# 
# LEF OUT 
# User Name : lonawu 
# Date : Thu Oct 12 15:11:58 2023
# 
VERSION 5.6 ;
BUSBITCHARS "[]" ;
DIVIDERCHAR "/" ;

UNITS
  DATABASE MICRONS 1000 ;
END UNITS
MANUFACTURINGGRID 0.001 ;

LAYER 3P
  TYPE MASTERSLICE ;
END 3P

LAYER 3N
  TYPE MASTERSLICE ;
END 3N

LAYER 2P
  TYPE MASTERSLICE ;
END 2P

LAYER 2N
  TYPE MASTERSLICE ;
END 2N

LAYER 1F_ACT
  TYPE MASTERSLICE ;
END 1F_ACT

LAYER 1G_GATE
  TYPE MASTERSLICE ;
END 1G_GATE

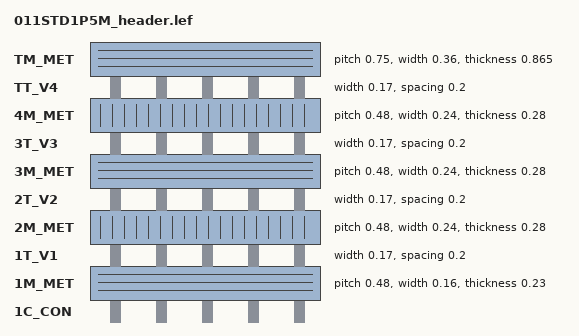
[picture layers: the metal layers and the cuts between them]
LAYER 1C_CON
  TYPE CUT ;
  WIDTH 0 ;
END 1C_CON

LAYER 1M_MET
  TYPE ROUTING ;
  DIRECTION HORIZONTAL ;
  PITCH 0.48 ;
  WIDTH 0.16 ;
  AREA 0.144 ;
  SPACINGTABLE 
    PARALLELRUNLENGTH    0      0      
      WIDTH 0           0.15   0.18   
      WIDTH 0.399       0.18   0.18   ;
  MINWIDTH 0.16 ;
  RESISTANCE RPERSQ 0.26 ;
  CAPACITANCE CPERSQDIST 4.7e-05 ;
  THICKNESS 0.23 ;
  ANTENNACUMAREARATIO 400 ;
  ANTENNACUMDIFFAREARATIO PWL ( ( 0 400 ) ( 0.2 400 ) ( 0.201 2280.4 ) ( 1.2 2680 )  ) ;
END 1M_MET

LAYER 1T_V1
  TYPE CUT ;
  SPACING 0.2 ;
  WIDTH 0.17 ;
  ANTENNACUMAREARATIO 20 ;
  ANTENNACUMDIFFAREARATIO PWL ( ( 0 20 ) ( 0.2 20 ) ( 0.201 1040.2 ) ( 1.2 1240 )  ) ;
END 1T_V1

LAYER 2M_MET
  TYPE ROUTING ;
  DIRECTION VERTICAL ;
  PITCH 0.48 ;
  WIDTH 0.24 ;
  AREA 0.144 ;
  SPACINGTABLE 
    PARALLELRUNLENGTH    0      0      0      
      WIDTH 0           0.24   0.3    0.56   
      WIDTH 0.999       0.3    0.3    0.56   
      WIDTH 9.999       0.56   0.56   0.56   ;
  MINWIDTH 0.24 ;
  RESISTANCE RPERSQ 0.19 ;
  CAPACITANCE CPERSQDIST 2.4e-05 ;
  THICKNESS 0.28 ;
  ANTENNACUMAREARATIO 400 ;
  ANTENNACUMDIFFAREARATIO PWL ( ( 0 400 ) ( 0.2 400 ) ( 0.201 2280.4 ) ( 1.2 2680 )  ) ;
END 2M_MET

LAYER 2T_V2
  TYPE CUT ;
  SPACING 0.2 ;
  WIDTH 0.17 ;
  ANTENNACUMAREARATIO 20 ;
  ANTENNACUMDIFFAREARATIO PWL ( ( 0 20 ) ( 0.2 20 ) ( 0.201 1040.2 ) ( 1.2 1240 )  ) ;
END 2T_V2

LAYER 3M_MET
  TYPE ROUTING ;
  DIRECTION HORIZONTAL ;
  PITCH 0.48 ;
  WIDTH 0.24 ;
  AREA 0.144 ;
  SPACINGTABLE 
    PARALLELRUNLENGTH    0      0      0      
      WIDTH 0           0.24   0.3    0.56   
      WIDTH 0.999       0.3    0.3    0.56   
      WIDTH 9.999       0.56   0.56   0.56   ;
  MINWIDTH 0.24 ;
  RESISTANCE RPERSQ 0.19 ;
  CAPACITANCE CPERSQDIST 1.5e-06 ;
  THICKNESS 0.28 ;
  ANTENNACUMAREARATIO 400 ;
  ANTENNACUMDIFFAREARATIO PWL ( ( 0 400 ) ( 0.2 400 ) ( 0.201 1280.4 ) ( 1.2 1680 )  ) ;
END 3M_MET

LAYER 3T_V3
  TYPE CUT ;
  SPACING 0.2 ;
  WIDTH 0.17 ;
  ANTENNACUMAREARATIO 20 ;
  ANTENNACUMDIFFAREARATIO PWL ( ( 0 20 ) ( 0.2 20 ) ( 0.201 1040.2 ) ( 1.2 1240 )  ) ;
END 3T_V3

LAYER 4M_MET
  TYPE ROUTING ;
  DIRECTION VERTICAL ;
  PITCH 0.48 ;
  WIDTH 0.24 ;
  AREA 0.144 ;
  SPACINGTABLE 
    PARALLELRUNLENGTH    0      0      0      
      WIDTH 0           0.24   0.3    0.56   
      WIDTH 0.999       0.3    0.3    0.56   
      WIDTH 9.999       0.56   0.56   0.56   ;
  MINWIDTH 0.24 ;
  RESISTANCE RPERSQ 0.19 ;
  CAPACITANCE CPERSQDIST 1.1e-06 ;
  THICKNESS 0.28 ;
  ANTENNACUMAREARATIO 400 ;
  ANTENNACUMDIFFAREARATIO PWL ( ( 0 400 ) ( 0.2 400 ) ( 0.201 1280.4 ) ( 1.2 1680 )  ) ;
END 4M_MET

LAYER TT_V4
  TYPE CUT ;
  SPACING 0.2 ;
  WIDTH 0.17 ;
  ANTENNACUMAREARATIO 20 ;
  ANTENNACUMDIFFAREARATIO PWL ( ( 0 20 ) ( 0.2 20 ) ( 0.201 1040.2 ) ( 1.2 1240 )  ) ;
END TT_V4

LAYER TM_MET
  TYPE ROUTING ;
  DIRECTION HORIZONTAL ;
  PITCH 0.75 ;
  WIDTH 0.36 ;
  AREA 0.562 ;
  SPACINGTABLE 
    PARALLELRUNLENGTH    0      0      
      WIDTH 0           0.39   0.6    
      WIDTH 9.999       0.6    0.6    ;
  MINWIDTH 0.36 ;
  RESISTANCE RPERSQ 0.04 ;
  CAPACITANCE CPERSQDIST 9.2e-06 ;
  THICKNESS 0.865 ;
  ANTENNACUMAREARATIO 400 ;
  ANTENNACUMDIFFAREARATIO PWL ( ( 0 400 ) ( 0.2 400 ) ( 0.201 11608 ) ( 1.2 19600 )  ) ;
END TM_MET

LAYER OverlapCheck
  TYPE OVERLAP ;
END OverlapCheck

VIA V12A
  DEFAULT 
  RESISTANCE 9.5 ;
  LAYER 1M_MET ;
    RECT -0.1350 -0.1350 0.1350 0.1350 ;
  LAYER 1T_V1 ;
    RECT -0.0850 -0.0850 0.0850 0.0850 ;
  LAYER 2M_MET ;
    RECT -0.1350 -0.1350 0.1350 0.1350 ;
END V12A

VIA V23A
  DEFAULT 
  RESISTANCE 9.5 ;
  LAYER 2M_MET ;
    RECT -0.1350 -0.1350 0.1350 0.1350 ;
  LAYER 2T_V2 ;
    RECT -0.0850 -0.0850 0.0850 0.0850 ;
  LAYER 3M_MET ;
    RECT -0.1350 -0.1350 0.1350 0.1350 ;
END V23A

VIA V34A
  DEFAULT 
  RESISTANCE 9.5 ;
  LAYER 3M_MET ;
    RECT -0.1350 -0.1350 0.1350 0.1350 ;
  LAYER 3T_V3 ;
    RECT -0.0850 -0.0850 0.0850 0.0850 ;
  LAYER 4M_MET ;
    RECT -0.1350 -0.1350 0.1350 0.1350 ;
END V34A

VIA V45A
  DEFAULT 
  RESISTANCE 3.6 ;
  LAYER 4M_MET ;
    RECT -0.2100 -0.2100 0.2100 0.2100 ;
  LAYER TT_V4 ;
    RECT -0.1100 -0.1100 0.1100 0.1100 ;
  LAYER TM_MET ;
    RECT -0.2100 -0.2100 0.2100 0.2100 ;
END V45A

VIARULE V12A GENERATE
  DEFAULT 
  LAYER 1M_MET ;
    ENCLOSURE 0.05 0.05 ;
  LAYER 2M_MET ;
    ENCLOSURE 0.05 0.05 ;
  LAYER 1T_V1 ;
    RECT -0.0850 -0.0850 0.0850 0.0850 ;
    SPACING 0.37 BY 0.37 ;
    RESISTANCE 9.5 ;
END V12A

VIARULE V23A GENERATE
  DEFAULT 
  LAYER 2M_MET ;
    ENCLOSURE 0.05 0.05 ;
  LAYER 3M_MET ;
    ENCLOSURE 0.05 0.05 ;
  LAYER 2T_V2 ;
    RECT -0.0850 -0.0850 0.0850 0.0850 ;
    SPACING 0.37 BY 0.37 ;
    RESISTANCE 9.5 ;
END V23A

VIARULE V34A GENERATE
  DEFAULT 
  LAYER 3M_MET ;
    ENCLOSURE 0.05 0.05 ;
  LAYER 4M_MET ;
    ENCLOSURE 0.05 0.05 ;
  LAYER 3T_V3 ;
    RECT -0.0850 -0.0850 0.0850 0.0850 ;
    SPACING 0.37 BY 0.37 ;
    RESISTANCE 9.5 ;
END V34A

VIARULE V45A GENERATE
  DEFAULT 
  LAYER 4M_MET ;
    ENCLOSURE 0.1 0.1 ;
  LAYER TM_MET ;
    ENCLOSURE 0.1 0.1 ;
  LAYER TT_V4 ;
    RECT -0.1100 -0.1100 0.1100 0.1100 ;
    SPACING 0.44 BY 0.44 ;
    RESISTANCE 3.6 ;
END V45A

SITE CORE
  CLASS CORE ;
  SYMMETRY X Y ;
  SIZE 0.48 BY 3.36 ;
END CORE
  
END LIBRARY
